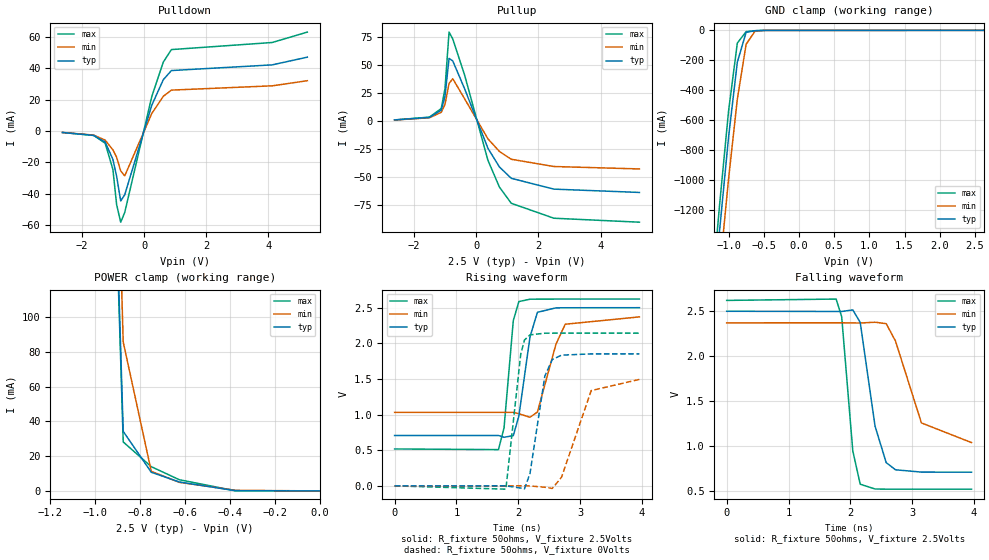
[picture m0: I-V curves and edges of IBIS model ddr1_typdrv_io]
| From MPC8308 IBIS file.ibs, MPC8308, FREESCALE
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[Model]   ddr1_typdrv_io   |
Model_type   I/O
Vinl = 1.22
Vinh = 1.28
Vmeas = 1.25
Cref = 1E-11
Rref = 50
Vref = 1.25
| variable   typ   min   max
C_comp   1.17p   1.10p   1.23p
[Model Spec]
| subparameter   typ   min   max
S_overshoot_high  3.300   3.135   3.465
S_overshoot_low   -200.00m  -100.00m  -300.00m
D_overshoot_high  4.000   4.000   4.000
D_overshoot_low   -1.000   -1.000   -1.000
D_overshoot_time  1.000n   1.000n   1.000n
| variable   typ   min   max
[Temperature Range]   25.0   -40.0   125.0
| variable   typ   min   max
[Pullup Reference]   2.500V   2.375V   2.625V
| variable   typ   min   max
[Pulldown Reference]   0.000V   0.000V   0.000V
| variable   typ   min   max
[POWER_Clamp_Reference]   2.500V   2.375V   2.625V
| variable   typ   min   max
[GND_Clamp_Reference]   0.000V   0.000V   0.000V
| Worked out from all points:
|   slope of the pulldown table from 0 to 0.375 V, typ, clamps not added: 16.5 ohm
|   slope of the pullup table from 0 to 0.375 V, typ, clamps not added: 15.6 ohm
|   GND clamp passes 1 mA (typ) near -0.53 V on its own axis
|   POWER clamp passes 1 mA (typ) near -0.42 V on its own axis
|   rising waveform, R_fixture 50ohms, V_fixture 2.5Volts: 20-80 % time 176ps typ, 237ps min, 123ps max; typ from 0.707 V to 2.5 V
|   rising waveform, R_fixture 50ohms, V_fixture 0Volts: 20-80 % time 188ps typ, 313ps min, 162ps max; typ from 0 V to 1.85 V
|   falling waveform, R_fixture 50ohms, V_fixture 2.5Volts: 20-80 % time 222ps typ, 350ps min, 143ps max; typ from 2.5 V to 0.707 V
[Pulldown]
| pulldown in the table = pulldown subtract gnd_clamp
|Voltage   I(typ)   I(min)   I(max)
-2.62V    -995.9uA   -962.3uA   -977.6uA
-1.62V    -2.836mA   -2.635mA   -2.849mA
-1.25V    -7.085mA   -5.845mA   -7.809mA
-1V       -18.2mA    -12.1mA    -24.63mA
-880mV    -29.11mA   -16.89mA   -47.18mA
-750mV    -44.77mA   -25.53mA   -58.35mA
-620mV    -40.81mA   -28.73mA   -52.12mA
250mV     16.51mA    11.21mA    22.03mA
620mV     32.79mA    22.18mA    44.06mA
880mV     38.64mA    26.13mA    52.05mA
4.12V     42.27mA    28.87mA    56.58mA
5.25V     47.21mA    32.14mA    63.24mA
[Pullup]
| pullup in the table = pullup subtract power_clamp
|Voltage   I(typ)   I(min)   I(max)
-2.62V    1.097mA    1.05mA     1.144mA
-1.5V     3.354mA    3.043mA    3.61mA
-1.12V    9.824mA    7.913mA    11.33mA
-1V       22.26mA    14.99mA    29.11mA
-870mV    56.06mA    33.69mA    79.57mA
-750mV    53.8mA     37.92mA    73.4mA
-370mV    28.96mA    20.02mA    41.24mA
380mV     -24.24mA   -15.78mA   -34.94mA
750mV     -40.9mA    -27.04mA   -58.88mA
1.13V     -51.02mA   -34.01mA   -73.32mA
2.5V      -60.69mA   -40.49mA   -86.68mA
5.25V     -63.65mA   -42.66mA   -90.22mA
[GND_clamp]
|Voltage   I(typ)   I(min)   I(max)
-2.625V   -9.755A    -9.951A    -9.643A
-1.25V    -1.981A    -2.246A    -1.82A
-1.125V   -1.325A    -1.6A      -1.154A
-1V       -714.6mA   -993.2mA   -540.4mA
-875mV    -212.1mA   -458.9mA   -84.78mA
-750mV    -13.33mA   -92.88mA   -8.382mA
-625mV    -2.595mA   -6.456mA   -2.637mA
-500mV    -493.4uA   -906.7uA   -363.8uA
2.625V    59.49nA    33.74uA    9.133pA
[POWER_clamp]
|Voltage   I(typ)   I(min)   I(max)
-2.375V   9.526A     9.538A     9.599A
-1.125V   1.078A     1.196A     1.069A
-875mV    34.28mA    85.75mA    28.2mA
-750mV    10.75mA    11.29mA    13.96mA
-625mV    5.151mA    4.938mA    6.448mA
-375mV    135.8uA    350uA      84.92uA
0V        255.3pA    14.06nA    16.83pA
[Ramp]
|Voltage   I(typ)   I(min)   I(max)
dV/dt_f   1.09/223.309p 0.81/354.977p 1.27/143.520p
dV/dt_r   1.14/191.378p 0.92/320.062p 1.31/123.945p
R_load=50ohms
| R_load was connected to ground for Ramp_up test and power for Ramp_dn test
[Rising_Waveform]
R_fixture=50ohms
V_fixture=2.5Volts
V_fixture_min=2.375Volts
V_fixture_max=2.625Volts
|C_fixture=1E-15f
|L_fixture=1E-15h
|C_dut=1E-15fh
|R_dut=0.001ohm
|L_dut=1E-12h
|time   V(typ)   V(min)   V(max)
0s        707mV      1.031V     518mV
1.68ns    707mV      1.031V     509mV
1.77ns    682mV      1.031V     813mV
1.92ns    705mV      1.032V     2.319V
2.01ns    980mV      1.012V     2.586V
2.19ns    2.09V      963mV      2.619V
2.31ns    2.435V     1.036V     2.62V
2.61ns    2.498V     1.988V     2.621V
2.76ns    2.499V     2.268V     2.621V
3.96ns    2.5V       2.371V     2.621V
[Rising_Waveform]
R_fixture=50ohms
V_fixture=0Volts
|C_fixture=1E-15f
|L_fixture=1E-15h
|C_dut=1E-15fh
|R_dut=0.001ohm
|L_dut=1E-12h
|time   V(typ)   V(min)   V(max)
0s        0V         0V         0V
1.8ns     1mV        0V         -46mV
2.04ns    -31mV      2mV        1.846V
2.1ns     -42mV      2mV        2.045V
2.19ns    174mV      -1mV       2.119V
2.43ns    1.54V      -19mV      2.142V
2.55ns    1.773V     -36mV      2.143V
2.7ns     1.834V     121mV      2.143V
3.18ns    1.852V     1.337V     2.143V
3.96ns    1.852V     1.494V     2.143V
[Falling_Waveform]
R_fixture=50ohms
V_fixture=2.5Volts
V_fixture_min=2.375Volts
V_fixture_max=2.625Volts
|C_fixture=1E-15f
|L_fixture=1E-15h
|C_dut=1E-15fh
|R_dut=0.001ohm
|L_dut=1E-12h
|time   V(typ)   V(min)   V(max)
0s        2.5V       2.371V     2.621V
1.77ns    2.498V     2.372V     2.636V
1.86ns    2.498V     2.372V     2.44V
2.04ns    2.515V     2.37V      943mV
2.16ns    2.376V     2.369V     573mV
2.4ns     1.219V     2.378V     520mV
2.58ns    814mV      2.362V     518mV
2.73ns    734mV      2.169V     518mV
3.15ns    708mV      1.256V     518mV
3.96ns    707mV      1.037V     518mV
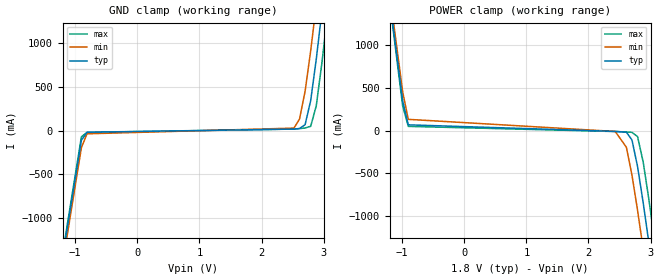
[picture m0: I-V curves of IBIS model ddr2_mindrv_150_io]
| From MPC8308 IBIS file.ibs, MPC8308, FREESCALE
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[Model]   ddr2_mindrv_150_io   |
Model_type   Input
Vinl = 0.87
Vinh = 0.93
| variable   typ   min   max
C_comp   1.17p   1.10p   1.23p
[Model Spec]
| subparameter   typ   min   max
S_overshoot_high  3.300   3.135   3.465
S_overshoot_low   -200.00m  -100.00m  -300.00m
D_overshoot_high  4.000   4.000   4.000
D_overshoot_low   -1.000   -1.000   -1.000
D_overshoot_time  1.000n   1.000n   1.000n
| variable   typ   min   max
[Temperature Range]   55.0   110.0   0.0
| variable   typ   min   max
[Pullup Reference]   1.800V   1.710V   1.890V
| variable   typ   min   max
[Pulldown Reference]   0.000V   0.000V   0.000V
| variable   typ   min   max
[POWER_Clamp_Reference]   1.800V   1.710V   1.890V
| variable   typ   min   max
[GND_Clamp_Reference]   0.000V   0.000V   0.000V
[GND_clamp]
|Voltage   I(typ)   I(min)   I(max)
-1.89V    -5.299A    -5.32A     -5.304A
-1.17V    -1.3A      -1.379A    -1.263A
-900mV    -110.7mA   -194.8mA   -71.07mA
-810mV    -19.66mA   -37.49mA   -21.41mA
2.52V     16.77mA    27.72mA    16.66mA
2.61V     22.76mA    130.3mA    22.06mA
2.7V      66.48mA    448.9mA    28.58mA
2.79V     342.7mA    912.2mA    48.37mA
2.88V     817.3mA    1.439A     284.2mA
2.97V     1.361A     1.997A     770.9mA
3.06V     1.934A     2.572A     1.329A
3.78V     6.8A       7.41A      6.204A
[POWER_clamp]
|Voltage   I(typ)   I(min)   I(max)
-1.89V    6.181A     6.181A     6.204A
-1.17V    1.361A     1.439A     1.329A
-990mV    342.7mA    448.9mA    284.2mA
-900mV    66.48mA    130.3mA    48.37mA
2.43V     -10.13mA   -10.88mA   -11.7mA
2.61V     -19.66mA   -194.8mA   -16.82mA
2.7V      -110.7mA   -521mA     -21.41mA
2.79V     -420.8mA   -930.8mA   -71.07mA
2.88V     -839.8mA   -1.379A    -365.6mA
2.97V     -1.3A      -1.847A    -793.6mA
3.06V     -1.779A    -2.327A    -1.263A
3.78V     -5.811A    -6.337A    -5.304A
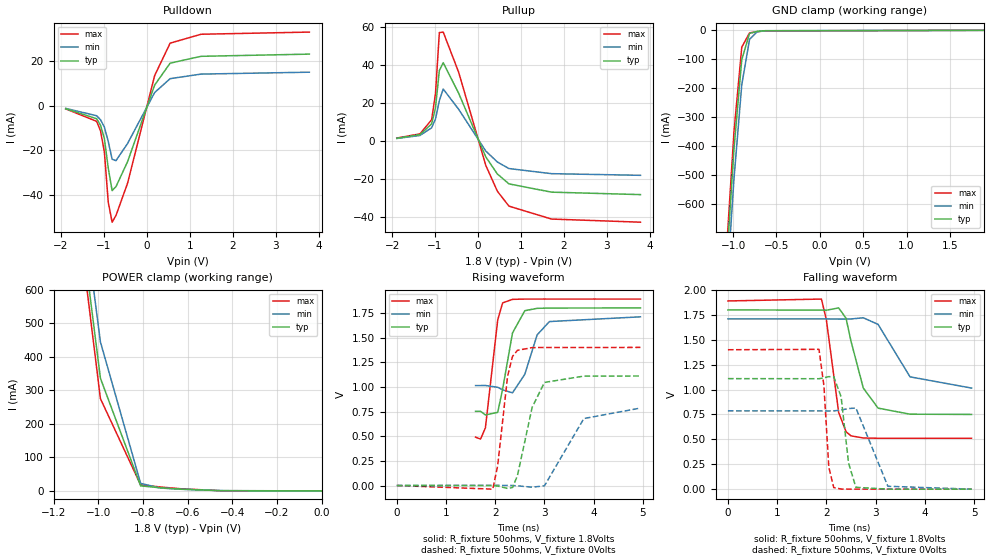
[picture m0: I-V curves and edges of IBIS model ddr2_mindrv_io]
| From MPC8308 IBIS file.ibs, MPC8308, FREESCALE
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[Model]   ddr2_mindrv_io   |
Model_type   I/O
Vinl = 0.87
Vinh = 0.93
Vmeas = 0.9
Cref = 1E-11
Rref = 50
Vref = 0.9
| variable   typ   min   max
C_comp   1.17p   1.10p   1.23p
[Model Spec]
| subparameter   typ   min   max
S_overshoot_high  3.300   3.135   3.465
S_overshoot_low   -200.00m  -100.00m  -300.00m
D_overshoot_high  4.000   4.000   4.000
D_overshoot_low   -1.000   -1.000   -1.000
D_overshoot_time  1.000n   1.000n   1.000n
| variable   typ   min   max
[Temperature Range]   25.0   -40.0   125.0
| variable   typ   min   max
[Pullup Reference]   1.800V   1.710V   1.890V
| variable   typ   min   max
[Pulldown Reference]   0.000V   0.000V   0.000V
| variable   typ   min   max
[POWER_Clamp_Reference]   1.800V   1.710V   1.890V
| variable   typ   min   max
[GND_Clamp_Reference]   0.000V   0.000V   0.000V
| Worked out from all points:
|   slope of the pulldown table from 0 to 0.27 V, typ, clamps not added: 21.1 ohm
|   slope of the pullup table from 0 to 0.27 V, typ, clamps not added: 22.8 ohm
|   GND clamp passes 1 mA (typ) near -0.59 V on its own axis
|   POWER clamp passes 1 mA (typ) near -0.47 V on its own axis
|   rising waveform, R_fixture 50ohms, V_fixture 1.8Volts: 20-80 % time 235ps typ, 284ps min, 184ps max; typ from 0.751 V to 1.8 V
|   rising waveform, R_fixture 50ohms, V_fixture 0Volts: 20-80 % time 305ps typ, 483ps min, 189ps max; typ from 0 V to 1.11 V
|   falling waveform, R_fixture 50ohms, V_fixture 1.8Volts: 20-80 % time 343ps typ, 500ps min, 224ps max; typ from 1.8 V to 0.75 V
|   falling waveform, R_fixture 50ohms, V_fixture 0Volts: 20-80 % time 154ps typ, 233ps min, 106ps max; typ from 1.11 V to 0 V
[Pulldown]
| pulldown in the table = pulldown subtract gnd_clamp
|Voltage   I(typ)   I(min)   I(max)
-1.89V    -1.33mA    -1.188mA   -1.404mA
-1.17V    -5.847mA   -4.504mA   -7.03mA
-1.08V    -8.788mA   -6.305mA   -11.33mA
-990mV    -14.82mA   -9.617mA   -20.83mA
-900mV    -28.12mA   -16.11mA   -43.49mA
-810mV    -38.25mA   -24.08mA   -52.47mA
-720mV    -36.44mA   -24.75mA   -49.43mA
-450mV    -25.18mA   -16.98mA   -34.89mA
180mV     9.323mA    5.97mA     13.61mA
540mV     19.2mA     12.22mA    28.21mA
1.26V     22.28mA    14.27mA    32.23mA
3.78V     23.27mA    15.13mA    33.2mA
[Pullup]
| pullup in the table = pullup subtract power_clamp
|Voltage   I(typ)   I(min)   I(max)
-1.89V    1.42mA     1.301mA    1.537mA
-1.35V    3.319mA    2.894mA    3.738mA
-1.08V    8.993mA    6.935mA    11.18mA
-990mV    17.4mA     11.56mA    24.89mA
-900mV    37.11mA    21.26mA    57.06mA
-810mV    41.22mA    27.34mA    57.32mA
-450mV    25.08mA    16.64mA    36.12mA
180mV     -8.375mA   -5.284mA   -12.84mA
450mV     -17.39mA   -11.09mA   -26.47mA
720mV     -22.6mA    -14.53mA   -34.33mA
1.71V     -26.95mA   -17.22mA   -41.12mA
3.78V     -28.25mA   -18.09mA   -42.77mA
[GND_clamp]
|Voltage   I(typ)   I(min)   I(max)
-1.89V    -5.289A    -5.314A    -5.291A
-1.08V    -830.5mA   -924.5mA   -780.6mA
-990mV    -411.5mA   -514.7mA   -352.7mA
-900mV    -101.5mA   -188.4mA   -58.29mA
-810mV    -10.46mA   -31.1mA    -8.864mA
-720mV    -3.532mA   -4.591mA   -4.66mA
-630mV    -1.451mA   -1.339mA   -1.97mA
1.89V     11.74nA    4.438uA    11.9pA
[POWER_clamp]
|Voltage   I(typ)   I(min)   I(max)
-1.71V    4.942A     4.957A     4.954A
-1.08V    811.3mA    908.1mA    762.8mA
-990mV    336.3mA    444.6mA    275.5mA
-810mV    15.09mA    22.51mA    17.99mA
-720mV    9.216mA    8.568mA    11.65mA
-630mV    5.341mA    4.938mA    6.448mA
-450mV    673.8uA    1mA        542.4uA
0V        210.7pA    7.657nA    11.9pA
[Ramp]
|Voltage   I(typ)   I(min)   I(max)
dV/dt_f   0.64/344.886p 0.43/506.533p 0.84/224.687p
dV/dt_r   0.69/311.081p 0.49/494.787p 0.86/192.911p
R_load=50ohms
| R_load was connected to ground for Ramp_up test and power for Ramp_dn test
[Rising_Waveform]
R_fixture=50ohms
V_fixture=1.8Volts
V_fixture_min=1.71Volts
V_fixture_max=1.89Volts
|C_fixture=1E-15f
|L_fixture=1E-15h
|C_dut=1E-15fh
|R_dut=0.001ohm
|L_dut=1E-12h
|time   V(typ)   V(min)   V(max)
1.6ns     751.5mV    1.013V     490.2mV
1.7ns     752.2mV    1.013V     470.4mV
1.8ns     715.8mV    1.014V     584.4mV
2.05ns    741.6mV    995.4mV    1.679V
2.15ns    977.2mV    969.8mV    1.851V
2.35ns    1.546V     939.5mV    1.887V
2.6ns     1.772V     1.127V     1.89V
2.85ns    1.796V     1.526V     1.89V
3.1ns     1.799V     1.662V     1.89V
4.95ns    1.8V       1.71V      1.89V
[Rising_Waveform]
R_fixture=50ohms
V_fixture=0Volts
|C_fixture=1E-15f
|L_fixture=1E-15h
|C_dut=1E-15fh
|R_dut=0.001ohm
|L_dut=1E-12h
|time   V(typ)   V(min)   V(max)
0s        8.982nV    834.4nV    106.7pV
1.95ns    -671.7uV   1.896mV    -37.1mV
2.05ns    -5.668mV   2.064mV    203.7mV
2.25ns    -29.94mV   1.071mV    1.107V
2.35ns    -20.94mV   -557.4uV   1.308V
2.45ns    98.77mV    -2.93mV    1.37V
2.75ns    793.4mV    -17.46mV   1.398V
3ns       1.045V     -2.482mV   1.399V
3.8ns     1.109V     679mV      1.399V
4.95ns    1.11V      784.9mV    1.4V
[Falling_Waveform]
R_fixture=50ohms
V_fixture=1.8Volts
V_fixture_min=1.71Volts
V_fixture_max=1.89Volts
|C_fixture=1E-15f
|L_fixture=1E-15h
|C_dut=1E-15fh
|R_dut=0.001ohm
|L_dut=1E-12h
|time   V(typ)   V(min)   V(max)
0s        1.8V       1.71V      1.89V
1.9ns     1.798V     1.71V      1.909V
2ns       1.797V     1.71V      1.701V
2.25ns    1.82V      1.708V     770.2mV
2.4ns     1.716V     1.708V     576.6mV
2.5ns     1.487V     1.709V     535.8mV
2.75ns    1.016V     1.721V     513.7mV
3.05ns    813.8mV    1.655V     511.3mV
3.7ns     753mV      1.128V     511.1mV
4.95ns    750.4mV    1.015V     511.1mV
[Falling_Waveform]
R_fixture=50ohms
V_fixture=0Volts
|C_fixture=1E-15f
|L_fixture=1E-15h
|C_dut=1E-15fh
|R_dut=0.001ohm
|L_dut=1E-12h
|time   V(typ)   V(min)   V(max)
0s        1.11V      786.4mV    1.4V
1.85ns    1.109V     786.3mV    1.404V
1.95ns    1.118V     785.8mV    1.04V
2.05ns    1.13V      785.5mV    220.8mV
2.15ns    1.129V     785.8mV    15.83mV
2.3ns     926.8mV    794.7mV    1.13mV
2.45ns    264.3mV    809.3mV    225.9uV
2.6ns     18.67mV    815mV      53.22uV
3.25ns    83.11uV    29mV       -184.3nV
4.95ns    -76.22nV   9.344uV    -25.64nV
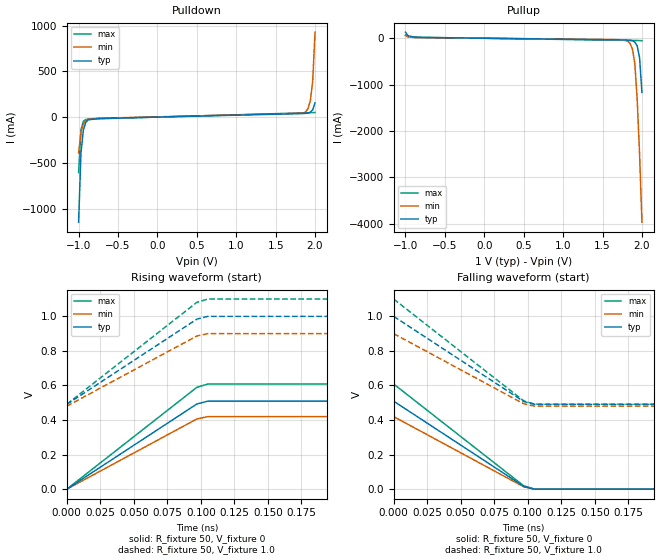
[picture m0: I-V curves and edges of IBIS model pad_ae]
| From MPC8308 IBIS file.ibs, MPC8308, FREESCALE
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[Model]   pad_ae
Model_type Output
Polarity Non-Inverting
Vmeas=0.5
C_comp   19.76fF   13.98fF   27.67fF
[Model Spec]
[Temperature Range] 65   125   -40
[Voltage Range]   1.0   0.9   1.1
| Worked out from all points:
|   slope of the pulldown table from 0 to 0.15 V, typ, clamps not added: 48.2 ohm
|   slope of the pullup table from 0 to 0.15 V, typ, clamps not added: 48.2 ohm
|   falling waveform, R_fixture 50, V_fixture 0: 20-80 % time 60ps typ, 60ps min, 60ps max; typ from 0.509 V to 0 V
|   falling waveform, R_fixture 50, V_fixture 1.0: 20-80 % time 60ps typ, 60ps min, 60ps max; typ from 1 V to 0.491 V
|   rising waveform, R_fixture 50, V_fixture 0: 20-80 % time 60ps typ, 60ps min, 60ps max; typ from 0 V to 0.509 V
|   rising waveform, R_fixture 50, V_fixture 1.0: 20-80 % time 60ps typ, 60ps min, 60ps max; typ from 0.491 V to 1 V
[Pullup]
-1V       133.5mA    59.71mA    67.8mA
-970mV    58.45mA    33.88mA    32.91mA
-880mV    19.77mA    16.48mA    21.86mA
1.67V     -34.66mA   -29.49mA   -41.34mA
1.76V     -36.69mA   -35.54mA   -43.56mA
1.82V     -39.28mA   -62.76mA   -45.05mA
1.85V     -42.95mA   -111.2mA   -45.79mA
1.88V     -52.73mA   -233.8mA   -46.54mA
1.91V     -80.91mA   -545.4mA   -47.3mA
1.94V     -164.5mA   -1.328A    -48.13mA
1.97V     -415.1mA   -2.487A    -49.32mA
2V        -1.168A    -3.967A    -52.3mA
[Pulldown]
-1V       -1.148A    -392.3mA   -606.7mA
-970mV    -394.3mA   -164mA     -141.3mA
-940mV    -143.8mA   -74.15mA   -46.9mA
-910mV    -60.16mA   -38.57mA   -27.29mA
-880mV    -31.97mA   -24.28mA   -22.74mA
-760mV    -15.94mA   -13.5mA    -18.81mA
1.85V     38.9mA     41.54mA    45.79mA
1.88V     40.52mA    55.82mA    46.53mA
1.91V     44.06mA    90.69mA    47.28mA
1.94V     53.28mA    177mA      48.03mA
1.97V     79.2mA     391.9mA    48.81mA
2V        154.3mA    928.2mA    49.73mA
[Falling Waveform]
R_fixture=50
V_fixture=0
V_fixture_min=0
V_fixture_max=0
0s        509.2mV    419.8mV    608.4mV
96.97ps   16.44mV    13.76mV    19.36mV
105.1ps   3.475uV    -6.738uV   -112.3nV
800ps     608.4fV    1.493pV    240.9fV
[Falling Waveform]
R_fixture=50
V_fixture=1.0
V_fixture_min=0.9
V_fixture_max=1.1
0s        1V         900mV      1.1V
96.97ps   507.2mV    493.9mV    510.9mV
105.1ps   490.8mV    480.2mV    491.6mV
800ps     490.8mV    480.2mV    491.6mV
[Rising Waveform]
R_fixture=50
V_fixture=0
V_fixture_min=0
V_fixture_max=0
0s        629.8fV    1.495pV    246fV
96.97ps   492.8mV    406.1mV    589.1mV
105.1ps   509.2mV    419.8mV    608.4mV
800ps     509.2mV    419.8mV    608.4mV
[Rising Waveform]
R_fixture=50
V_fixture=1.0
V_fixture_min=0.9
V_fixture_max=1.1
0s        490.8mV    480.2mV    491.6mV
96.97ps   983.6mV    886.2mV    1.081V
105.1ps   1V         900mV      1.1V
800ps     1V         900mV      1.1V
[Ramp]
R_load=50
dV/dt_r   3.055E-1/6.000E-11   2.519E-1/6.000E-11   3.650E-1/6.000E-11
dV/dt_f   3.055E-1/6.000E-11   2.519E-1/6.000E-11   3.650E-1/6.000E-11
|[End   pad_ae
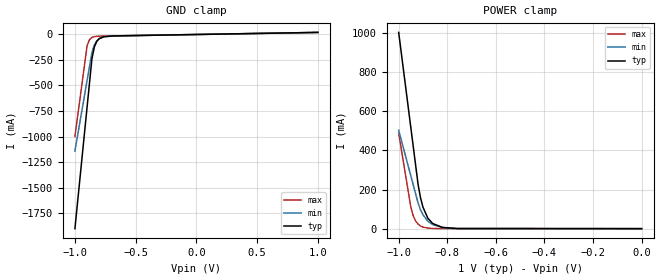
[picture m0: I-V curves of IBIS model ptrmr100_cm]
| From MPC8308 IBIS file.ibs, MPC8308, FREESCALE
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[Model]   ptrmr100_cm
Model_type Input
Polarity Non-Inverting
Vinh=0.8
Vinl=0.2
C_comp   400f   400f   400f
[Temperature Range] 65   125   -40
[Voltage Range]   1.0   0.9   1.1
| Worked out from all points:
|   GND clamp passes 1 mA (typ) near -0.05 V on its own axis
|   POWER clamp passes 1 mA (typ) near -0.77 V on its own axis
[GND Clamp]
-1V       -1.903A    -1.142A    -999.6mA
-900mV    -713.2mA   -452.2mA   -111.5mA
-880mV    -475.2mA   -314.4mA   -50.14mA
-860mV    -237.2mA   -176.5mA   -28.7mA
-840mV    -122.7mA   -102.3mA   -21.02mA
-820mV    -67.56mA   -62.38mA   -18.08mA
-800mV    -40.86mA   -40.76mA   -16.77mA
-760mV    -21.31mA   -22.45mA   -15.5mA
-680mV    -14.26mA   -14.31mA   -13.75mA
1V        20.3mA     19.9mA     20.12mA
[POWER Clamp]
-1V       1.004A     503.4mA    488.6mA
-950mV    517.4mA    270.3mA    110mA
-940mV    420mA      223.7mA    65.22mA
-930mV    322.7mA    177.1mA    38.69mA
-920mV    225.4mA    130.5mA    22.97mA
-910mV    157.4mA    96.1mA     13.65mA
-900mV    109.9mA    70.76mA    8.12mA
-880mV    53.67mA    38.31mA    2.874mA
-860mV    26.21mA    20.66mA    1.014mA
-820mV    6.233mA    5.864mA    120.3uA
-760mV    678.3uA    692uA      0A
0V        0A         0A         0A
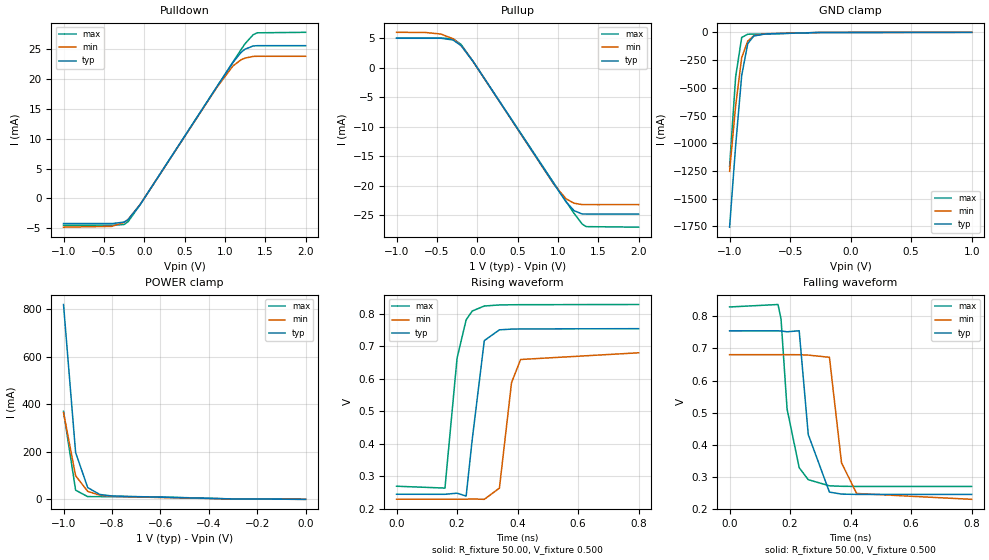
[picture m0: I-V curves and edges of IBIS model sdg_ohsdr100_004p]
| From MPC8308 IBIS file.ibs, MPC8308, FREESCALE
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[Model]   sdg_ohsdr100_004p
Model_type 3-state
Enable Active-High
Polarity Non-Inverting
|   TYP   MIN   MAX
C_comp   1.60pF   1.60pF   1.67pF
[Model Spec]
Vmeas   0.5   0.45   0.55
[Voltage Range]   1.0   0.9   1.1
[Temperature Range] 65   125   -40
[Driver Schedule]
| Model_Name  Rise_on_dly   Rise_off_dly   Fall_on_dly   Fall_off_dly
sdg_ohsdr100_00   0ps   NA   0ps   NA
sdg_ohsdr100_04   400ps   NA   400ps   NA
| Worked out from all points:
|   slope of the pulldown table from 0 to 0.15 V, typ, clamps not added: 48.2 ohm
|   slope of the pullup table from 0 to 0.15 V, typ, clamps not added: 48.2 ohm
|   GND clamp passes 1 mA (typ) near -0.22 V on its own axis
|   POWER clamp passes 1 mA (typ) near -0.25 V on its own axis
|   falling waveform, R_fixture 50.00, V_fixture 0.500: 20-80 % time 34ps typ, 36.1ps min, 37.8ps max; typ from 0.755 V to 0.245 V
|   rising waveform, R_fixture 50.00, V_fixture 0.500: 20-80 % time 28.6ps typ, 33.2ps min, 33.6ps max; typ from 0.245 V to 0.754 V
[Pullup]
|   Vout(V)   TYP   WCS   BCS
-1V       4.969mA    5.972mA    5.004mA
-650mV    4.969mA    5.953mA    5.004mA
-450mV    4.969mA    5.681mA    5.004mA
-300mV    4.672mA    4.885mA    4.893mA
-200mV    3.728mA    3.75mA     3.921mA
-50mV     1.018mA    1.012mA    1.029mA
950mV     -19.66mA   -19.74mA   -19.53mA
1.1V      -22.68mA   -22.18mA   -22.61mA
1.2V      -24.19mA   -22.93mA   -24.65mA
1.3V      -24.75mA   -23.17mA   -26.44mA
1.35V     -24.76mA   -23.17mA   -26.89mA
2V        -24.76mA   -23.17mA   -26.98mA
[Pulldown]
|   Vout(V)   TYP   WCS   BCS
-1V       -4.19mA    -4.788mA   -4.477mA
-400mV    -4.19mA    -4.655mA   -4.477mA
-250mV    -3.952mA   -3.99mA    -4.352mA
-200mV    -3.545mA   -3.503mA   -3.884mA
-50mV     -1.016mA   -1.002mA   -1.031mA
900mV     18.63mA    18.53mA    18.64mA
1.1V      22.7mA     22.13mA    22.78mA
1.2V      24.38mA    23.15mA    24.84mA
1.25V     24.93mA    23.44mA    25.84mA
1.35V     25.46mA    23.72mA    27.33mA
1.4V      25.51mA    23.74mA    27.66mA
2V        25.51mA    23.74mA    27.74mA
[GND Clamp]
|   Vout(V)   TYP   WCS   BCS
-1V       -1.756A    -1.253A    -1.21A
-950mV    -1.023A    -662.4mA   -401.5mA
-900mV    -388.6mA   -227.9mA   -46.1mA
-850mV    -101.9mA   -79.16mA   -16.82mA
-800mV    -32.57mA   -30.94mA   -16.19mA
-700mV    -13.95mA   -12.54mA   -14.94mA
-250mV    -1.344mA   -1.319mA   -914.3uA
1V        14.57uA    95.41uA    1.385uA
[POWER Clamp]
|   Vout(V)   TYP   WCS   BCS
-1V       820.3mA    365.3mA    370.7mA
-950mV    197mA      99.34mA    38.49mA
-900mV    49.45mA    33.55mA    11.42mA
-850mV    20.38mA    17.36mA    11.35mA
-800mV    14.23mA    12.73mA    11.26mA
-600mV    8.918mA    7.602mA    10.02mA
-300mV    1.728mA    1.566mA    1.457mA
0V        0A         0A         0A
[Falling Waveform]
R_fixture=50.00
V_fixture=0.500
V_fixture_min=0.450
V_fixture_max=0.550
|   t(s)   TYP   WCS   BCS
0s        754.7mV    680.5mV    829.1mV
160ps     754.8mV    680.5mV    836.8mV
170ps     754.4mV    680.5mV    791.7mV
190ps     751.8mV    680.5mV    511.2mV
230ps     755.1mV    680.4mV    328.7mV
260ps     431.8mV    679.2mV    291.2mV
330ps     252.5mV    672.4mV    272.1mV
370ps     246.3mV    343.3mV    270.6mV
420ps     245.3mV    248.2mV    270.1mV
800ps     245.3mV    230mV      270mV
[Rising Waveform]
R_fixture=50.00
V_fixture=0.500
V_fixture_min=0.450
V_fixture_max=0.550
|   t(s)   TYP   WCS   BCS
0s        245.3mV    230mV      270mV
160ps     245.2mV    230mV      264.3mV
200ps     248.6mV    230mV      663.8mV
230ps     239.7mV    230.1mV    781.6mV
250ps     412.4mV    230.9mV    808.7mV
290ps     717.7mV    229.7mV    824.2mV
340ps     750.9mV    264.2mV    827.4mV
380ps     753.1mV    588.2mV    828mV
410ps     753.6mV    659.7mV    828.2mV
800ps     754.5mV    680.3mV    828.8mV
[Ramp]
R_load=50.00
dV/dt_r  3.0563e-01/2.7501e-11  2.7585e-01/3.2692e-11  3.3540e-01/3.3179e-11
dV/dt_f  3.0564e-01/3.3393e-11  2.7586e-01/3.5723e-11  3.3542e-01/3.7500e-11
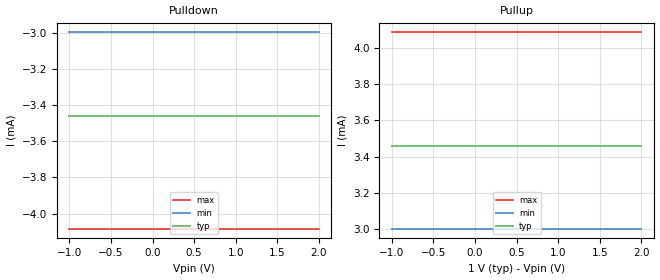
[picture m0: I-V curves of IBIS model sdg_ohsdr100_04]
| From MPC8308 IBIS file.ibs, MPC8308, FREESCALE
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[Model]   sdg_ohsdr100_04
Model_type 3-state
Enable Active-High
Polarity Non-Inverting
|   TYP   MIN   MAX
C_comp   0.00pF   0.00pF   0.00pF
[Model Spec]
Vmeas   0.5   0.45   0.55
[Temperature Range] 65   125   -40
[Voltage Range]   1.0   0.9   1.1
[Pullup]
|   Vout(V)   TYP   WCS   BCS
-1V       3.458mA    3.002mA    4.086mA
2V        3.458mA    3.002mA    4.086mA
[Pulldown]
|   Vout(V)   TYP   WCS   BCS
-1V       -3.458mA   -2.999mA   -4.083mA
2V        -3.458mA   -2.999mA   -4.083mA
[GND Clamp]
|   Vout(V)   TYP   WCS   BCS
-1V       0A         0A         0A
1V        0A         0A         0A
[POWER Clamp]
|   Vout(V)   TYP   WCS   BCS
-1V       0A         0A         0A
0V        0A         0A         0A
[Ramp]
R_load=50
dV/dt_r  3.0563e-01/2.7501e-11  2.7585e-01/3.2692e-11  3.3540e-01/3.3179e-11
dV/dt_f  3.0564e-01/3.3393e-11  2.7586e-01/3.5723e-11  3.3542e-01/3.7500e-11
|[End   sdg_ohsdr100_04
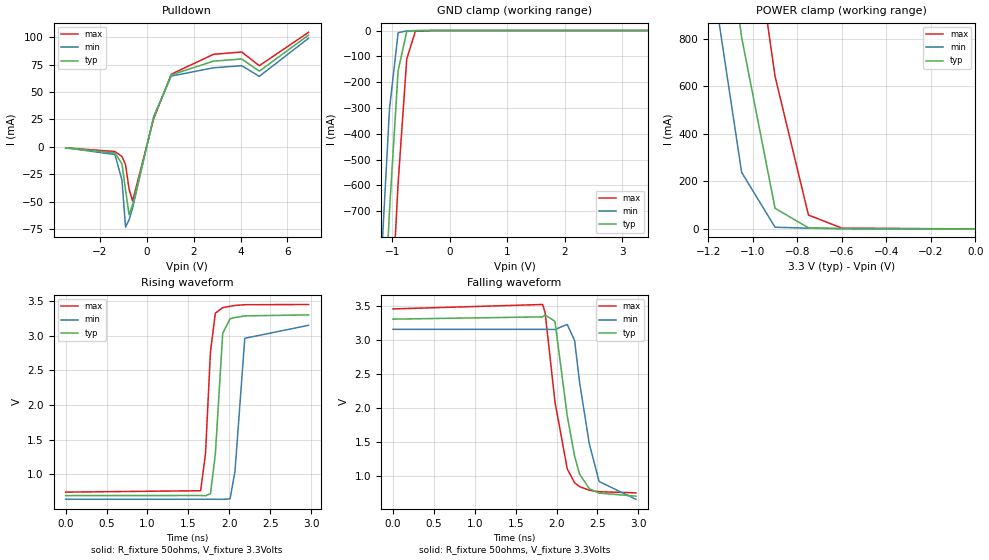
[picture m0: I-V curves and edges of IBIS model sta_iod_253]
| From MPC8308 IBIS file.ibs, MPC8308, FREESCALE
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[Model]   sta_iod_253   |
Model_type   I/O_open_drain
Vinl = 0.8
Vinh = 2
Vmeas = 1.65
Cref = 5E-11
Rref = 50
Vref = 1.65
| variable   typ   min   max
C_comp   494.81f   465.60f   523.27f
[Model Spec]
| subparameter   typ   min   max
S_overshoot_high  3.300   3.135   3.465
S_overshoot_low   -200.00m  -100.00m  -300.00m
D_overshoot_high  4.000   4.000   4.000
D_overshoot_low   -1.000   -1.000   -1.000
D_overshoot_time  1.000n   1.000n   1.000n
| variable   typ   min   max
[Temperature Range]   55.0   110.0   0.0
| variable   typ   min   max
[Pullup Reference]   3.300V   3.150V   3.450V
| variable   typ   min   max
[Pulldown Reference]   0.000V   0.000V   0.000V
| variable   typ   min   max
[POWER_Clamp_Reference]   3.300V   3.150V   3.450V
| variable   typ   min   max
[GND_Clamp_Reference]   0.000V   0.000V   0.000V
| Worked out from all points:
|   slope of the pulldown table from 0 to 0.495 V, typ, clamps not added: 12.4 ohm
|   GND clamp passes 1 mA (typ) near -0.62 V on its own axis
|   POWER clamp passes 1 mA (typ) near -0.51 V on its own axis
|   rising waveform, R_fixture 50ohms, V_fixture 3.3Volts: 20-80 % time 74.9ps typ, 76.6ps min, 71.7ps max; typ from 0.695 V to 3.3 V
|   falling waveform, R_fixture 50ohms, V_fixture 3.3Volts: 20-80 % time 201ps typ, 204ps min, 185ps max; typ from 3.3 V to 0.698 V
[Pulldown]
| pulldown in the table = pulldown subtract gnd_clamp
|Voltage   I(typ)   I(min)   I(max)
-3.45V    -872.5uA   -841.3uA   -848.6uA
-1.35V    -5.535mA   -6.95mA    -4.235mA
-1.05V    -15.56mA   -30.43mA   -8.792mA
-900mV    -39.07mA   -73.08mA   -16.14mA
-750mV    -61.82mA   -66.44mA   -38.16mA
-600mV    -52.74mA   -55.84mA   -49.36mA
300mV     26.56mA    27.73mA    25.65mA
1.05V     65.58mA    64.47mA    66.21mA
2.85V     78.08mA    71.99mA    84.3mA
4.05V     80.02mA    73.94mA    86.37mA
4.8V      68.94mA    64.22mA    73.92mA
6.9V      101.8mA    98.94mA    104.3mA
[GND_clamp]
|Voltage   I(typ)   I(min)   I(max)
-3.45V    -12.31A    -11.88A    -12.85A
-1.2V     -1.358A    -924.9mA   -1.906A
-1.05V    -698.5mA   -303.5mA   -1.226A
-900mV    -155.7mA   -8.533mA   -591.6mA
-750mV    -3.954mA   -1.306mA   -110.3mA
-600mV    -606.2uA   -198.8uA   -3.05mA
-300mV    -1.971uA   -109.9nA   -16.38uA
3.45V     171.4nA    873.4nA    35.1nA
[POWER_clamp]
|Voltage   I(typ)   I(min)   I(max)
-3.3V     18.63A     17.95A     19.5A
-1.2V     1.853A     1.171A     2.731A
-1.05V    806.1mA    238.2mA    1.631A
-900mV    87.08mA    7.341mA    642.4mA
-750mV    4.847mA    3.182mA    58.69mA
-600mV    1.868mA    967.7uA    3.546mA
0V        962.3pA    16.62pA    35.1nA
[Ramp]
|Voltage   I(typ)   I(min)   I(max)
dV/dt_f   1.61/204.357p 1.55/208.211p 1.68/187.372p
dV/dt_r   1.56/130.543p 1.51/134.827p 1.63/125.396p
R_load=50ohms
| R_load was connected to gnd in Ramp_up and power in Ramp_dn tests
[Rising_Waveform]
R_fixture=50ohms
V_fixture=3.3Volts
V_fixture_min=3.15Volts
V_fixture_max=3.45Volts
|C_fixture=1E-15f
|L_fixture=1E-15h
|C_dut=1E-15fh
|R_dut=0.001ohm
|L_dut=1E-12h
|time   V(typ)   V(min)   V(max)
0s        695mV      642mV      745mV
1.65ns    696mV      642mV      765mV
1.71ns    693mV      642mV      1.303V
1.77ns    722mV      642mV      2.765V
1.83ns    1.29V      642mV      3.325V
1.92ns    3.034V     641mV      3.404V
2.01ns    3.245V     648mV      3.425V
2.07ns    3.262V     1.042V     3.436V
2.19ns    3.286V     2.963V     3.447V
2.97ns    3.3V       3.15V      3.45V
[Falling_Waveform]
R_fixture=50ohms
V_fixture=3.3Volts
V_fixture_min=3.15Volts
V_fixture_max=3.45Volts
|C_fixture=1E-15f
|L_fixture=1E-15h
|C_dut=1E-15fh
|R_dut=0.001ohm
|L_dut=1E-12h
|time   V(typ)   V(min)   V(max)
0s        3.3V       3.15V      3.45V
1.83ns    3.333V     3.15V      3.515V
1.86ns    3.361V     3.15V      3.391V
1.98ns    3.267V     3.148V     2.084V
2.13ns    1.878V     3.222V     1.1V
2.22ns    1.286V     2.987V     895mV
2.28ns    1.024V     2.379V     838mV
2.4ns     806mV      1.466V     785mV
2.52ns    742mV      913mV      763mV
2.97ns    698mV      651mV      746mV
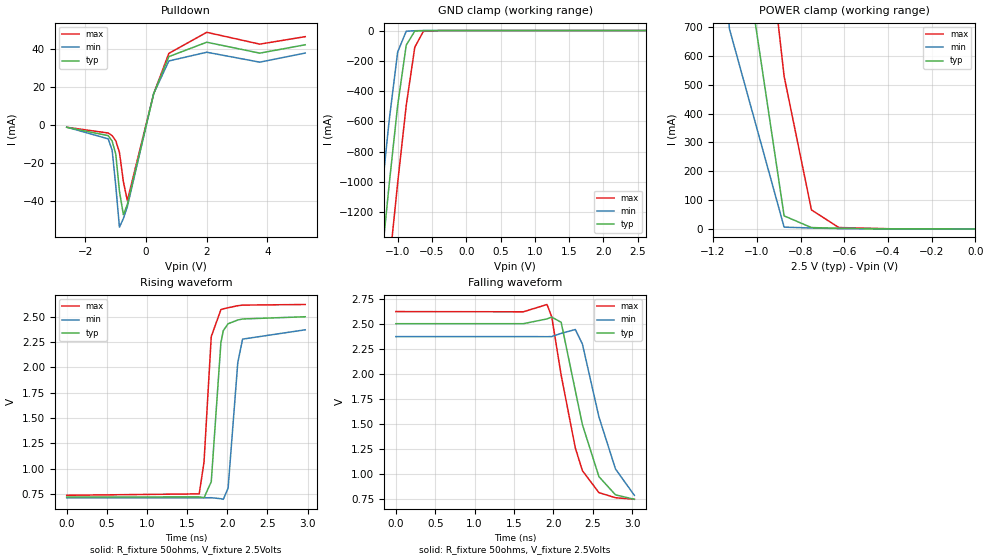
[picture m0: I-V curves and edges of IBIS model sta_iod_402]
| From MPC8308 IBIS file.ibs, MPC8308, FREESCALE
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[Model]   sta_iod_402   |
Model_type   I/O_open_drain
Vinl = 0.8
Vinh = 2
Vmeas = 1.25
Cref = 5E-11
Rref = 50
Vref = 1.25
| variable   typ   min   max
C_comp   494.81f   465.60f   523.27f
[Model Spec]
| subparameter   typ   min   max
S_overshoot_high  3.300   3.135   3.465
S_overshoot_low   -200.00m  -100.00m  -300.00m
D_overshoot_high  4.000   4.000   4.000
D_overshoot_low   -1.000   -1.000   -1.000
D_overshoot_time  1.000n   1.000n   1.000n
| variable   typ   min   max
[Temperature Range]   55.0   110.0   0.0
| variable   typ   min   max
[Pullup Reference]   2.500V   2.375V   2.625V
| variable   typ   min   max
[Pulldown Reference]   0.000V   0.000V   0.000V
| variable   typ   min   max
[POWER_Clamp_Reference]   2.500V   2.375V   2.625V
| variable   typ   min   max
[GND_Clamp_Reference]   0.000V   0.000V   0.000V
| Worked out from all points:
|   slope of the pulldown table from 0 to 0.375 V, typ, clamps not added: 16.4 ohm
|   GND clamp passes 1 mA (typ) near -0.63 V on its own axis
|   POWER clamp passes 1 mA (typ) near -0.48 V on its own axis
|   rising waveform, R_fixture 50ohms, V_fixture 2.5Volts: 20-80 % time 87.1ps typ, 87ps min, 81.6ps max; typ from 0.719 V to 2.5 V
|   falling waveform, R_fixture 50ohms, V_fixture 2.5Volts: 20-80 % time 308ps typ, 318ps min, 281ps max; typ from 2.5 V to 0.743 V
[Pulldown]
| pulldown in the table = pulldown subtract gnd_clamp
|Voltage   I(typ)   I(min)   I(max)
-2.62V    -980.6uA   -928.8uA   -959.8uA
-1.25V    -5.372mA   -7.06mA    -3.992mA
-1.12V    -8.257mA   -13.1mA    -5.417mA
-1V       -15.14mA   -31.95mA   -8.109mA
-880mV    -34.61mA   -53.51mA   -14.15mA
-750mV    -46.99mA   -48.96mA   -29.57mA
-620mV    -41.65mA   -42.75mA   -39.54mA
250mV     16.7mA     16.71mA    16.7mA
750mV     36.19mA    33.91mA    37.9mA
2V        43.77mA    38.5mA     48.97mA
3.75V     38.02mA    33.28mA    42.76mA
5.25V     42.42mA    38.06mA    46.69mA
[GND_clamp]
|Voltage   I(typ)   I(min)   I(max)
-2.625V   -8.238A    -7.809A    -8.789A
-1.375V   -2.169A    -1.729A    -2.725A
-1.25V    -1.587A    -1.15A     -2.138A
-1.125V   -1.022A    -599.6mA   -1.562A
-1V       -495.7mA   -142mA     -1.007A
-875mV    -96.85mA   -4.727mA   -495mA
-750mV    -3.954mA   -1.306mA   -110.3mA
-625mV    -811.4uA   -299.3uA   -5.426mA
-375mV    -11.43uA   -1.052uA   -68.06uA
2.625V    73.92nA    174.2nA    36.56nA
[POWER_clamp]
|Voltage   I(typ)   I(min)   I(max)
-2.375V   11.13A     10.48A     12.06A
-1.125V   1.313A     693.4mA    2.21A
-875mV    45.26mA    6.278mA    529.2mA
-750mV    4.847mA    3.274mA    66.07mA
-625mV    2.231mA    1.317mA    4.96mA
-375mV    89.99uA    11.17uA    418uA
0V        786.4pA    14.16pA    36.56nA
[Ramp]
|Voltage   I(typ)   I(min)   I(max)
dV/dt_f   1.11/322.756p 1.04/353.573p 1.18/288.537p
dV/dt_r   1.06/165.048p 0.99/172.850p 1.12/155.615p
R_load=50ohms
| R_load was connected to ground for Ramp_up test and power for Ramp_dn test
[Rising_Waveform]
R_fixture=50ohms
V_fixture=2.5Volts
V_fixture_min=2.375Volts
V_fixture_max=2.625Volts
|C_fixture=1E-15f
|L_fixture=1E-15h
|C_dut=1E-15fh
|R_dut=0.001ohm
|L_dut=1E-12h
|time   V(typ)   V(min)   V(max)
0s        719mV      711mV      736mV
1.65ns    720mV      711mV      750mV
1.71ns    712mV      711mV      1.065V
1.8ns     870mV      712mV      2.304V
1.92ns    2.243V     702mV      2.57V
1.95ns    2.363V     696mV      2.578V
2.01ns    2.431V     808mV      2.589V
2.13ns    2.468V     2.044V     2.609V
2.19ns    2.478V     2.279V     2.615V
2.97ns    2.5V       2.371V     2.621V
[Falling_Waveform]
R_fixture=50ohms
V_fixture=2.5Volts
V_fixture_min=2.375Volts
V_fixture_max=2.625Volts
|C_fixture=1E-15f
|L_fixture=1E-15h
|C_dut=1E-15fh
|R_dut=0.001ohm
|L_dut=1E-12h
|time   V(typ)   V(min)   V(max)
0s        2.5V       2.371V     2.621V
1.62ns    2.5V       2.371V     2.619V
1.92ns    2.548V     2.37V      2.692V
1.98ns    2.566V     2.371V     2.57V
2.1ns     2.514V     2.403V     1.985V
2.28ns    1.83V      2.442V     1.257V
2.37ns    1.49V      2.296V     1.03V
2.58ns    970mV      1.567V     810mV
2.79ns    788mV      1.047V     759mV
3.03ns    743mV      783mV      744mV
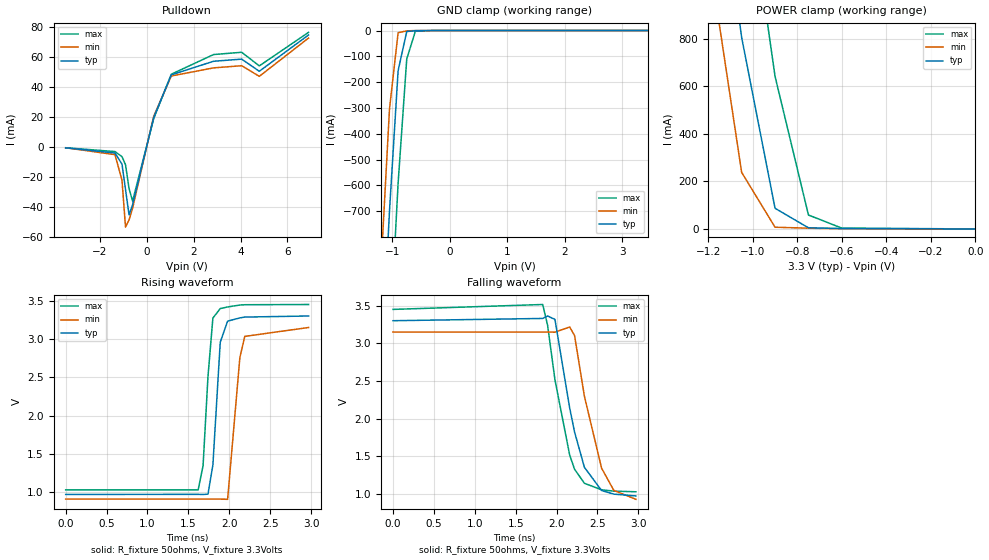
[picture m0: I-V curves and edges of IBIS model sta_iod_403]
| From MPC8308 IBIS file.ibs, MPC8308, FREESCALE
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[Model]   sta_iod_403   |
Model_type   I/O_open_drain
Vinl = 0.8
Vinh = 2
Vmeas = 1.65
Cref = 5E-11
Rref = 50
Vref = 1.65
| variable   typ   min   max
C_comp   494.81f   465.60f   523.27f
[Model Spec]
| subparameter   typ   min   max
S_overshoot_high  3.300   3.135   3.465
S_overshoot_low   -200.00m  -100.00m  -300.00m
D_overshoot_high  4.000   4.000   4.000
D_overshoot_low   -1.000   -1.000   -1.000
D_overshoot_time  1.000n   1.000n   1.000n
| variable   typ   min   max
[Temperature Range]   55.0   110.0   0.0
| variable   typ   min   max
[Pullup Reference]   3.300V   3.150V   3.450V
| variable   typ   min   max
[Pulldown Reference]   0.000V   0.000V   0.000V
| variable   typ   min   max
[POWER_Clamp_Reference]   3.300V   3.150V   3.450V
| variable   typ   min   max
[GND_Clamp_Reference]   0.000V   0.000V   0.000V
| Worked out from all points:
|   slope of the pulldown table from 0 to 0.495 V, typ, clamps not added: 16.8 ohm
|   GND clamp passes 1 mA (typ) near -0.62 V on its own axis
|   POWER clamp passes 1 mA (typ) near -0.51 V on its own axis
|   rising waveform, R_fixture 50ohms, V_fixture 3.3Volts: 20-80 % time 77.3ps typ, 77.7ps min, 75.6ps max; typ from 0.972 V to 3.3 V
|   falling waveform, R_fixture 50ohms, V_fixture 3.3Volts: 20-80 % time 256ps typ, 262ps min, 237ps max; typ from 3.3 V to 0.977 V
[Pulldown]
| pulldown in the table = pulldown subtract gnd_clamp
|Voltage   I(typ)   I(min)   I(max)
-3.45V    -644.6uA   -622.1uA   -626.2uA
-1.35V    -4.132mA   -5.207mA   -3.151mA
-1.05V    -11.56mA   -22.33mA   -6.546mA
-900mV    -28.51mA   -53.69mA   -11.94mA
-750mV    -45.44mA   -48.92mA   -27.87mA
-600mV    -38.8mA    -41.13mA   -36.25mA
300mV     19.54mA    20.42mA    18.85mA
1.05V     48.13mA    47.36mA    48.56mA
2.85V     57.21mA    52.8mA     61.7mA
4.05V     58.64mA    54.24mA    63.22mA
4.8V      50.53mA    47.13mA    54.12mA
6.9V      74.81mA    72.75mA    76.56mA
[GND_clamp]
|Voltage   I(typ)   I(min)   I(max)
-3.45V    -12.31A    -11.88A    -12.85A
-1.2V     -1.358A    -924.9mA   -1.906A
-1.05V    -698.5mA   -303.5mA   -1.226A
-900mV    -155.7mA   -8.533mA   -591.6mA
-750mV    -3.954mA   -1.306mA   -110.3mA
-600mV    -606.2uA   -198.8uA   -3.05mA
-300mV    -1.971uA   -109.9nA   -16.38uA
3.45V     171.4nA    873.4nA    35.1nA
[POWER_clamp]
|Voltage   I(typ)   I(min)   I(max)
-3.3V     18.63A     17.95A     19.5A
-1.2V     1.853A     1.171A     2.731A
-1.05V    806.1mA    238.2mA    1.631A
-900mV    87.08mA    7.341mA    642.4mA
-750mV    4.847mA    3.182mA    58.69mA
-600mV    1.868mA    967.7uA    3.546mA
0V        962.3pA    16.62pA    35.1nA
[Ramp]
|Voltage   I(typ)   I(min)   I(max)
dV/dt_f   1.44/261.275p 1.38/269.625p 1.50/241.645p
dV/dt_r   1.40/74.121p 1.35/75.565p 1.46/72.699p
R_load=50ohms
| R_load was connected to power in Ramp_up and Ramp_dn tests
[Rising_Waveform]
R_fixture=50ohms
V_fixture=3.3Volts
V_fixture_min=3.15Volts
V_fixture_max=3.45Volts
|C_fixture=1E-15f
|L_fixture=1E-15h
|C_dut=1E-15fh
|R_dut=0.001ohm
|L_dut=1E-12h
|time   V(typ)   V(min)   V(max)
0s        972mV      911mV      1.031V
1.62ns    973mV      911mV      1.031V
1.68ns    971mV      911mV      1.348V
1.74ns    976mV      911mV      2.512V
1.8ns     1.356V     912mV      3.273V
1.89ns    2.958V     911mV      3.397V
1.98ns    3.233V     908mV      3.418V
2.13ns    3.275V     2.759V     3.443V
2.19ns    3.286V     3.034V     3.447V
2.97ns    3.3V       3.15V      3.45V
[Falling_Waveform]
R_fixture=50ohms
V_fixture=3.3Volts
V_fixture_min=3.15Volts
V_fixture_max=3.45Volts
|C_fixture=1E-15f
|L_fixture=1E-15h
|C_dut=1E-15fh
|R_dut=0.001ohm
|L_dut=1E-12h
|time   V(typ)   V(min)   V(max)
0s        3.3V       3.15V      3.45V
1.83ns    3.33V      3.15V      3.515V
1.89ns    3.363V     3.15V      3.239V
1.98ns    3.317V     3.148V     2.515V
2.16ns    2.143V     3.217V     1.518V
2.22ns    1.823V     3.102V     1.33V
2.34ns    1.356V     2.298V     1.145V
2.55ns    1.049V     1.345V     1.058V
2.7ns     1.001V     1.05V      1.041V
2.97ns    977mV      932mV      1.032V
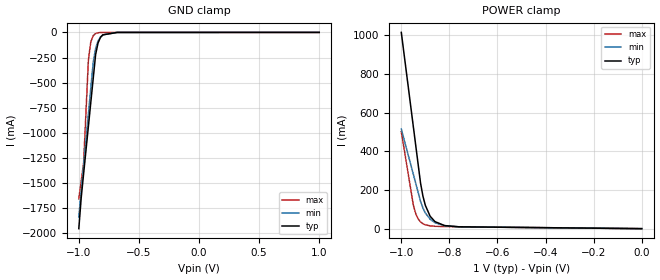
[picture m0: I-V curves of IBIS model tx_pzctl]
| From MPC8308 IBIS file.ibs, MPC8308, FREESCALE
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[Model]   tx_pzctl
Model_type Input
Vinh=0.8
Vinl=0.2
C_comp   1.62pF   1.61pF   1.63pf
[Model Spec]
[Temperature Range] 65   125   -40
[Voltage Range]   1.0   0.9   1.1
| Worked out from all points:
|   GND clamp passes 1 mA (typ) near -0.71 V on its own axis
|   POWER clamp passes 1 mA (typ) near -0.10 V on its own axis
[GND Clamp]
-1V       -1.952A    -1.835A    -1.655A
-980mV    -1.645A    -1.579A    -1.478A
-960mV    -1.407A    -1.322A    -1.3A
-920mV    -932mA     -809.3mA   -270.1mA
-900mV    -694.4mA   -552.9mA   -92.97mA
-880mV    -456.9mA   -296.5mA   -32.03mA
-860mV    -219.3mA   -159mA     -11.05mA
-840mV    -105.3mA   -85.31mA   -3.812mA
-820mV    -50.58mA   -45.76mA   -1.305mA
-800mV    -24.31mA   -24.53mA   -432uA
-680mV    -256.9uA   -483.8uA   0A
1V        0A         0A         0A
[POWER Clamp]
-1V       1.016A     515.6mA    501.6mA
-950mV    528.6mA    281.8mA    122.5mA
-940mV    431.2mA    235.1mA    77.56mA
-930mV    333.7mA    188.3mA    50.91mA
-920mV    236.3mA    141.5mA    35.07mA
-910mV    168.2mA    107mA      25.63mA
-900mV    120.6mA    81.53mA    19.96mA
-880mV    64.1mA     48.78mA    14.44mA
-860mV    36.4mA     30.84mA    12.27mA
-820mV    15.93mA    15.47mA    10.72mA
-760mV    9.587mA    9.459mA    9.584mA
0V        125.8nA    177.7nA    338.6nA
